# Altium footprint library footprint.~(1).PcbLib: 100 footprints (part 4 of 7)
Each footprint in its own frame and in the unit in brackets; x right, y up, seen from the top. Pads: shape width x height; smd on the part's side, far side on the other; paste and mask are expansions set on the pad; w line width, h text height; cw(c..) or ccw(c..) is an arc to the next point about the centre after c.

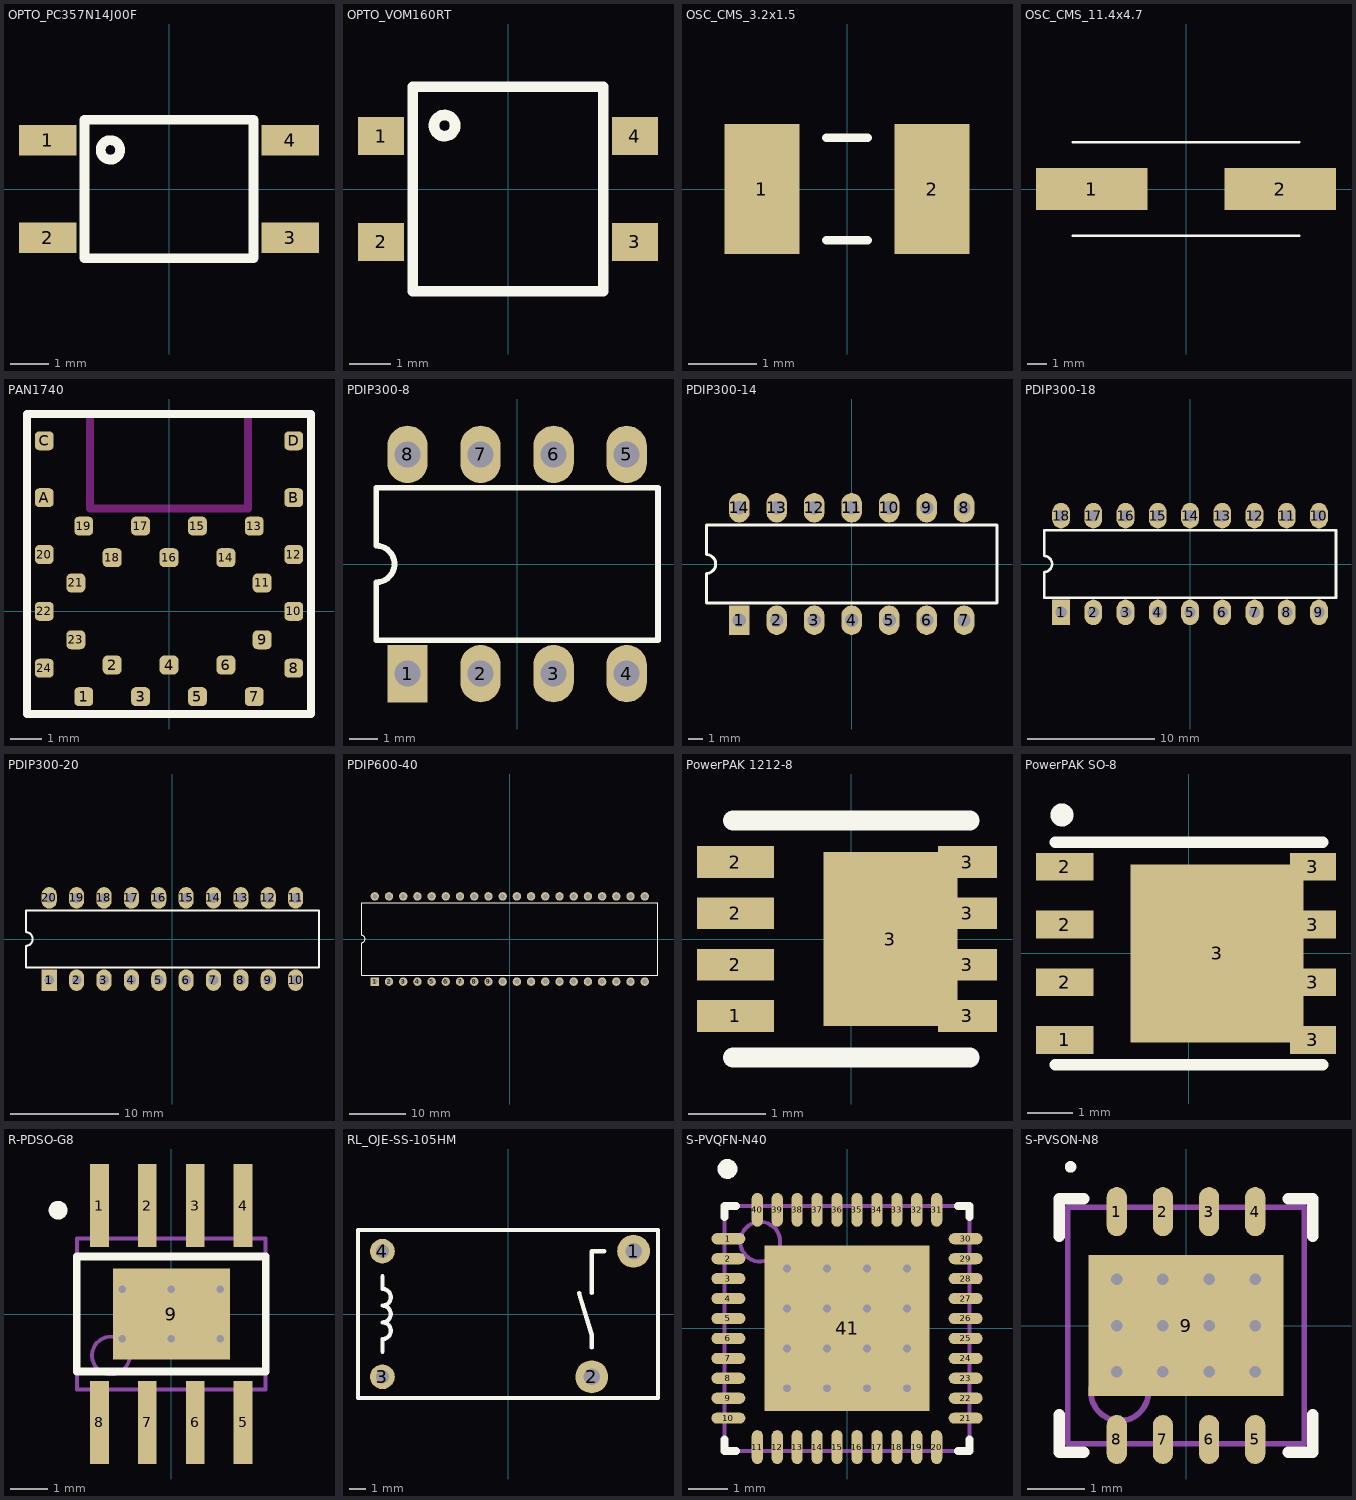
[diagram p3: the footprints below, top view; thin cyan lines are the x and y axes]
## OPTO_PC357N14J00F [mm] "optocoupleur"
height 2.6
pads (4):
  rect 1.5x0.8 smd: 1(-3.15,1.27) 2(-3.15,-1.27) 3(3.15,-1.27) 4(3.15,1.27)
Top Overlay:
  circle w0.254: c-1.524,1.016 r0.254
  lines w0.254: -2.2,-1.8 2.2,-1.8 2.2,1.8 -2.2,1.8 -2.2,-1.8
3D body: height 2.6, standoff 0, extent -2.2,-1.8 2.2,1.8

## OPTO_VOM160RT [mm] "Opto-triac"
height 1.97
pads (4):
  rect 1.11x0.91 smd: 1(-3.048,1.27) 2(-3.048,-1.27) 3(3.048,-1.27) 4(3.048,1.27)
Top Overlay:
  circle w0.254: c-1.524,1.524 r0.254
  lines w0.254: -2.285,-2.46 -2.285,2.46 2.285,2.46 2.285,-2.46 -2.285,-2.46
3D body: height 1.97, standoff 0, extent -2.285,-2.46 2.285,2.46

## OSC_CMS_3.2x1.5 [mm] "quartz CMS 3.2x1.5mm"
height 0.9
pads (2):
  rect 1.1x1.9 smd: 1(-1.25,0) 2(1.25,0)
Top Overlay:
  lines w0.127: -0.3,-0.75 0.3,-0.75 ; -0.3,0.75 0.3,0.75
3D body: height 0.9, standoff 0, extent -1.6,-0.75 1.6,0.75

## OSC_CMS_11.4x4.7 [mm] "quartz CMS 11.4x4.7mm"
height 4.2
pads (2):
  rect 5.6x2.1 smd: 1(-4.75,0) 2(4.75,0)
Top Overlay:
  lines w0.127: -5.7,-2.35 5.7,-2.35 ; -5.7,2.35 5.7,2.35
3D body: height 0.9, standoff 0, extent -5.7,-2.35 5.7,2.35

## PAN1740 [mm] "DA14580 bluetooth low energy module"
height 1.8
pads (28):
  rrect50% 0.6x0.6 smd: 1(-2.7,-2.7) 2(-1.8,-1.7) 3(-0.9,-2.7) 4(0,-1.7) 5(0.9,-2.7) 6(1.8,-1.7) 7(2.7,-2.7) 8(3.95,-1.8) 9(2.95,-0.9) 10(3.95,0) 11(2.95,0.9) 12(3.95,1.8) 13(2.7,2.7) 14(1.8,1.7) 15(0.9,2.7) 16(0,1.7) 17(-0.9,2.7) 18(-1.8,1.7) 19(-2.7,2.7) 20(-3.95,1.8) 21(-2.95,0.9) 22(-3.95,0) 23(-2.95,-0.9) 24(-3.95,-1.8) A(-3.95,3.6) B(3.95,3.6) C(-3.95,5.4) D(3.95,5.4)
Top Overlay:
  lines w0.254: -4.5,-3.25 -4.5,6.25 4.5,6.25 4.5,-3.25 -4.5,-3.25
Keep-Out Layer:
  lines w0.254: -2.5,3.25 2.5,3.25 2.5,6.25 -2.5,6.25 -2.5,3.25

## PDIP300-8 [mm] "DIP, Plastic; 8 Leads; Row Spacing 7.62 mm; Pitch 2.54 mm"
height 4.32
pads (8):
  rect 1.4x2 hole 0.9: 1(-3.81,-3.81)
  oval 1.4x2 hole 0.9: 2(-1.27,-3.81) 3(1.27,-3.81) 4(3.81,-3.81) 5(3.81,3.81) 6(1.27,3.81) 7(-1.27,3.81) 8(-3.81,3.81)
Top Overlay:
  lines w0.2: -4.9,-2.65 -4.9,-0.635 ccw(c-4.9,0) -4.9,0.635 -4.9,2.65 4.9,2.65 4.9,-2.65 -4.9,-2.65

## PDIP300-14 [mm] "DIP, Plastic; 14 Leads; Row Spacing 7.62 mm; Pitch 2.54 mm"
height 4.32
pads (14):
  rect 1.4x2 hole 0.9: 1(-7.62,-3.81)
  oval 1.4x2 hole 0.9: 2(-5.08,-3.81) 3(-2.54,-3.81) 4(0,-3.81) 5(2.54,-3.81) 6(5.08,-3.81) 7(7.62,-3.81) 8(7.62,3.81) 9(5.08,3.81) 10(2.54,3.81) 11(0,3.81) 12(-2.54,3.81) 13(-5.08,3.81) 14(-7.62,3.81)
Top Overlay:
  lines w0.2: -9.85,-2.65 -9.85,-0.635 ccw(c-9.85,0) -9.85,0.635 -9.85,2.65 9.85,2.65 9.85,-2.65 -9.85,-2.65

## PDIP300-18 [mm] "DIP, Plastic; 18 Leads; Row Spacing 7.62 mm; Pitch 2.54 mm"
height 4.32
pads (18):
  rect 1.4x2 hole 0.9: 1(-10.16,-3.81)
  oval 1.4x2 hole 0.9: 2(-7.62,-3.81) 3(-5.08,-3.81) 4(-2.54,-3.81) 5(0,-3.81) 6(2.54,-3.81) 7(5.08,-3.81) 8(7.62,-3.81) 9(10.16,-3.81) 10(10.16,3.81) 11(7.62,3.81) 12(5.08,3.81) 13(2.54,3.81) 14(0,3.81) 15(-2.54,3.81) 16(-5.08,3.81) 17(-7.62,3.81) 18(-10.16,3.81)
Top Overlay:
  lines w0.2: -11.5,-2.65 -11.5,-0.635 ccw(c-11.5,0) -11.5,0.635 -11.5,2.65 11.5,2.65 11.5,-2.65 -11.5,-2.65

## PDIP300-20 [mm] "DIP, Plastic; 20 Leads; Row Spacing 7.62 mm; Pitch 2.54 mm"
height 4.32
pads (20):
  rect 1.4x2 hole 0.9: 1(-11.43,-3.81)
  oval 1.4x2 hole 0.9: 2(-8.89,-3.81) 3(-6.35,-3.81) 4(-3.81,-3.81) 5(-1.27,-3.81) 6(1.27,-3.81) 7(3.81,-3.81) 8(6.35,-3.81) 9(8.89,-3.81) 10(11.43,-3.81) 11(11.43,3.81) 12(8.89,3.81) 13(6.35,3.81) 14(3.81,3.81) 15(1.27,3.81) 16(-1.27,3.81) 17(-3.81,3.81) 18(-6.35,3.81) 19(-8.89,3.81) 20(-11.43,3.81)
Top Overlay:
  lines w0.2: -13.6,-2.65 -13.6,-0.635 ccw(c-13.6,0) -13.6,0.635 -13.6,2.65 13.6,2.65 13.6,-2.65 -13.6,-2.65

## PDIP600-40 [mm] "DIP, Plastic; 40 Leads; Row Spacing 15.24 mm; Pitch 2.54 mm"
height 4.83
pads (40):
  rect 1.5x1.5 hole 0.9: 1(-24.13,-7.62)
  round 1.5 hole 0.9: 2(-21.59,-7.62) 3(-19.05,-7.62) 4(-16.51,-7.62) 5(-13.97,-7.62) 6(-11.43,-7.62) 7(-8.89,-7.62) 8(-6.35,-7.62) 9(-3.81,-7.62) 10(-1.27,-7.62) 11(1.27,-7.62) 12(3.81,-7.62) 13(6.35,-7.62) 14(8.89,-7.62) 15(11.43,-7.62) 16(13.97,-7.62) 17(16.51,-7.62) 18(19.05,-7.62) 19(21.59,-7.62) 20(24.13,-7.62) 21(24.13,7.62) 22(21.59,7.62) 23(19.05,7.62) 24(16.51,7.62) 25(13.97,7.62) 26(11.43,7.62) 27(8.89,7.62) 28(6.35,7.62) 29(3.81,7.62) 30(1.27,7.62) 31(-1.27,7.62) 32(-3.81,7.62) 33(-6.35,7.62) 34(-8.89,7.62) 35(-11.43,7.62) 36(-13.97,7.62) 37(-16.51,7.62) 38(-19.05,7.62) 39(-21.59,7.62) 40(-24.13,7.62)
Top Overlay:
  lines w0.2: -26.5,-6.45 26.5,-6.45 26.5,6.45 -26.5,6.45 -26.5,0.635 cw(c-26.5,0) -26.5,-0.635 -26.5,-6.45

## PowerPAK 1212-8 [mil] "Vishay PowerPAK 1212-8"
height 40.94
pads (9):
  rect 39x16 smd: 1(-58.75,-39) 2(-58.75,-13) 2(-58.75,13) 2(-58.75,39)
  rect 68x88 smd: 3(19.75,0)
  rect 30x16 smd: 3(58.75,-39) 3(58.75,-13) 3(58.75,13) 3(58.75,39)
Top Overlay:
  lines w10: -60,-60 60,-60 ; -60,60 60,60
3D body: height 41, standoff 0, extent -60,-60 60,60

## PowerPAK SO-8 [mil] "Vishay PowerPAK SO-8"
height 40.94
pads (9):
  rect 50x24 smd: 1(-107.5,-75) 2(-107.5,-25) 2(-107.5,25) 2(-107.5,75)
  rect 150x154 smd: 3(24.5,0)
  rect 40x24 smd: 3(107.5,-75) 3(107.5,-25) 3(107.5,25) 3(107.5,75)
Top Overlay:
  circle w10: c-110,120 r5
  lines w10: -116,-96.5 116,-96.5 ; -116,96.5 116,96.5
3D body: height 41, standoff 0, extent -116,-96.5 116,96.5

## R-PDSO-G8 [mm] "SOIC, 8-Leads, Body 4,90x3,90mm, Pitch 1,27mm, Thermal Pad 3,10x2,40mm, IPC Medium Density"
height 1.7
pads (9):
  rect 0.5x2.2 smd: 1(-1.905,2.875) 2(-0.635,2.875) 3(0.635,2.875) 4(1.905,2.875) 5(1.905,-2.875) 6(0.635,-2.875) 7(-0.635,-2.875) 8(-1.905,-2.875)
  rect 3.1x2.4 smd paste+0: 9(0,0)
via 1.3,0.65 diameter 0.5 hole 0.2
via 1.3,-0.65 diameter 0.5 hole 0.2
via 0,0.65 diameter 0.5 hole 0.2
via 0,-0.65 diameter 0.5 hole 0.2
via -1.3,0.65 diameter 0.5 hole 0.2
via -1.3,-0.65 diameter 0.5 hole 0.2
Top Overlay:
  circle w0.25: c-3,2.75 r0.125
  lines w0.2: -2.5,-1.524 -2.5,1.524 2.5,1.524 2.5,-1.524 -2.5,-1.524
Mechanical 13:
  circle w0.1: c-1.6,-1.1 r0.5
  lines w0.1: -2.5,-2 -2.5,2 2.5,2 2.5,-2 -2.5,-2
3D body: height 1.7, standoff 0, extent -2.5,-2 2.5,2

## RL_OJE-SS-105HM [mm] "Relais 5V 10A SPST"
height 14.6
pads (4):
  round 2 hole 1: 1(7.62,3.81) 2(5.08,-3.81)
  round 1.5 hole 0.8: 3(-7.62,-3.81) 4(-7.62,3.81)
Top Overlay:
  lines w0.254: -7.62,-2.286 -7.62,-1.524 ccw(c-7.62,-1.016) -7.62,-0.508 ccw(c-7.62,0) -7.62,0.508 ccw(c-7.62,1.016) -7.62,1.524 -7.62,2.286 ; 4.318,1.27 5.08,-1.27 5.08,-2.032 ; 5.08,1.27 5.08,3.81 5.842,3.81 ; -9.1,-5.1 -9.1,5.1 9.1,5.1 9.1,-5.1 -9.1,-5.1
3D body: height 14.6, standoff 0, extent -9.1,-5.1 9.1,5.1

## S-PVQFN-N40 [mm] "VQFN, 40-Leads, Body 6,00x6,00mm, Pitch 0,50mm, Thermal Pad 4,92x4,92mm, IPC Medium Density"
height 1
pads (41):
  oval 0.85x0.28 smd: 1(-2.975,2.25) 2(-2.975,1.75) 3(-2.975,1.25) 4(-2.975,0.75) 5(-2.975,0.25) 6(-2.975,-0.25) 7(-2.975,-0.75) 8(-2.975,-1.25) 9(-2.975,-1.75) 10(-2.975,-2.25) 21(2.975,-2.25) 22(2.975,-1.75) 23(2.975,-1.25) 24(2.975,-0.75) 25(2.975,-0.25) 26(2.975,0.25) 27(2.975,0.75) 28(2.975,1.25) 29(2.975,1.75) 30(2.975,2.25)
  oval 0.28x0.85 smd: 11(-2.25,-2.975) 12(-1.75,-2.975) 13(-1.25,-2.975) 14(-0.75,-2.975) 15(-0.25,-2.975) 16(0.25,-2.975) 17(0.75,-2.975) 18(1.25,-2.975) 19(1.75,-2.975) 20(2.25,-2.975) 31(2.25,2.975) 32(1.75,2.975) 33(1.25,2.975) 34(0.75,2.975) 35(0.25,2.975) 36(-0.25,2.975) 37(-0.75,2.975) 38(-1.25,2.975) 39(-1.75,2.975) 40(-2.25,2.975)
  rect 4.15x4.15 smd paste-2.075: 41(0,0)
via -0.5,-0.5 diameter 0.5 hole 0.2
via 1.5,-1.5 diameter 0.5 hole 0.2
via 0.5,-1.5 diameter 0.5 hole 0.2
via -0.5,-1.5 diameter 0.5 hole 0.2
via -1.5,-1.5 diameter 0.5 hole 0.2
via 1.5,-0.5 diameter 0.5 hole 0.2
via 0.5,-0.5 diameter 0.5 hole 0.2
via -1.5,-0.5 diameter 0.5 hole 0.2
via 1.5,0.5 diameter 0.5 hole 0.2
via 0.5,0.5 diameter 0.5 hole 0.2
via -0.5,0.5 diameter 0.5 hole 0.2
via -1.5,0.5 diameter 0.5 hole 0.2
via 1.5,1.5 diameter 0.5 hole 0.2
via 0.5,1.5 diameter 0.5 hole 0.2
via -0.5,1.5 diameter 0.5 hole 0.2
via -1.5,1.5 diameter 0.5 hole 0.2
Top Overlay:
  circle w0.25: c-3,4 r0.125
  lines w0.2: -3.075,-2.79 -3.075,-3.075 -2.79,-3.075 ; -3.075,2.79 -3.075,3.075 -2.79,3.075 ; 2.79,-3.075 3.075,-3.075 3.075,-2.79 ; 2.79,3.075 3.075,3.075 3.075,2.79
Top Paste:
  rectangle: -0.575,-2.025 0.575,-0.875
  rectangle: 0.875,-2.025 2.025,-0.875
  rectangle: -2.025,-2.025 -0.875,-0.875
  rectangle: -2.025,-0.575 -0.875,0.575
  rectangle: -2.025,0.875 -0.875,2.025
  rectangle: 0.875,0.875 2.025,2.025
  rectangle: -0.575,0.875 0.575,2.025
  rectangle: 0.875,-0.525 2.025,0.625
  rectangle: -0.575,-0.575 0.575,0.575
Mechanical 13:
  circle w0.1: c-2.175,2.175 r0.5
  lines w0.1: -3.075,-3.075 3.075,-3.075 3.075,3.075 -3.075,3.075 -3.075,-3.075
3D body: height 1, standoff 0, extent -3.075,-3.075 3.075,3.075

## S-PVSON-N8 [mm] "VSON, 8-Leads, Body 4,00x4,00mm, Pitch 0,80mm, Thermal Pad 3,38x2,45mm, IPC Medium Density"
height 1
pads (9):
  oval 0.35x0.85 smd: 1(-1.2,1.975) 2(-0.4,1.975) 3(0.4,1.975) 4(1.2,1.975) 5(1.2,-1.975) 6(0.4,-1.975) 7(-0.4,-1.975) 8(-1.2,-1.975)
  rect 3.38x2.45 smd paste-1.225: 9(0,0)
via -1.2,0 diameter 0.5 hole 0.2
via -1.2,0.8 diameter 0.5 hole 0.2
via -0.4,0.8 diameter 0.5 hole 0.2
via 0.4,0 diameter 0.5 hole 0.2
via 0.4,0.8 diameter 0.5 hole 0.2
via -0.4,0 diameter 0.5 hole 0.2
via 1.2,0.8 diameter 0.5 hole 0.2
via 1.2,0 diameter 0.5 hole 0.2
via 1.2,-0.8 diameter 0.5 hole 0.2
via 0.4,-0.8 diameter 0.5 hole 0.2
via -0.4,-0.8 diameter 0.5 hole 0.2
via -1.2,-0.8 diameter 0.5 hole 0.2
Top Overlay:
  circle w0.1: c-2,2.75 r0.05
  lines w0.2: -2.2,-1.545 -2.2,-2.2 -1.775,-2.2 ; -2.2,1.545 -2.2,2.2 -1.775,2.2 ; 1.775,-2.2 2.2,-2.2 2.2,-1.545 ; 1.775,2.2 2.2,2.2 2.2,1.545
Top Paste:
  rectangle: 0.15,0.15 1.65,1.15
  rectangle: 0.15,-1.15 1.65,-0.15
  rectangle: -1.65,-1.15 -0.15,-0.15
  rectangle: -1.65,0.15 -0.15,1.15
Mechanical 13:
  circle w0.1: c-1.15,-1.15 r0.5
  lines w0.1: -2.05,-2.05 2.05,-2.05 2.05,2.05 -2.05,2.05 -2.05,-2.05
3D body: height 1, standoff 0, extent -2.05,-2.05 2.05,2.05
